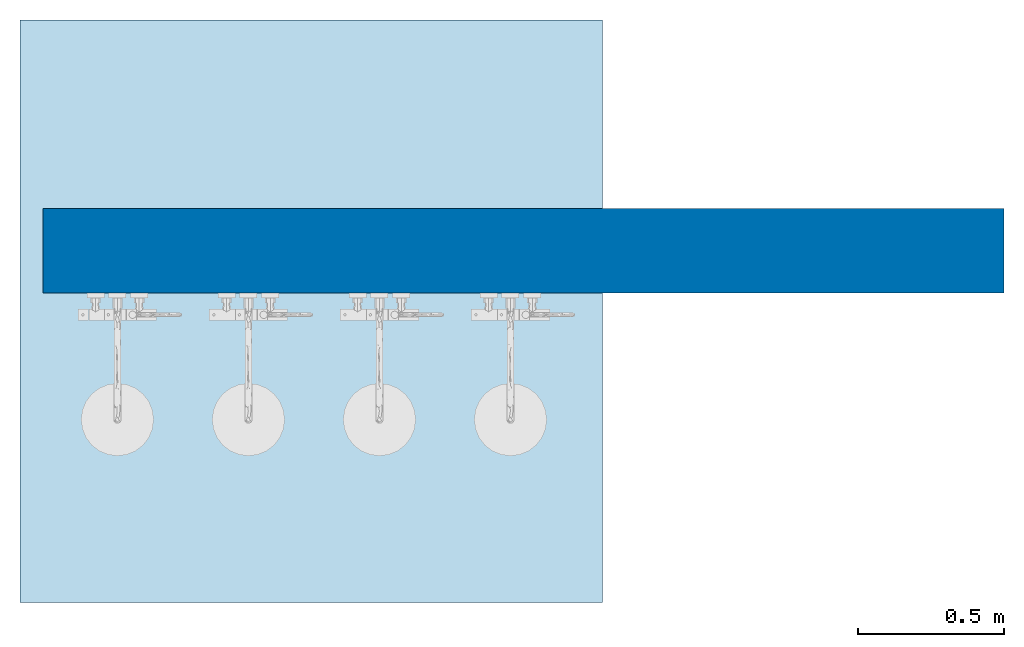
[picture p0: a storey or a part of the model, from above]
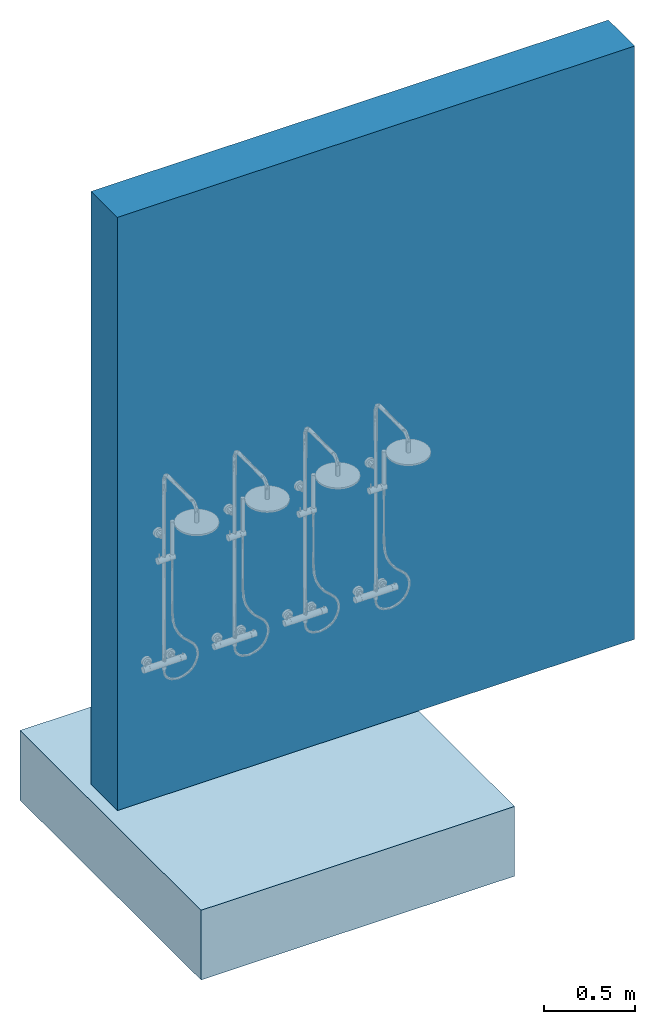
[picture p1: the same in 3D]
Properties of the parts of a building model (IFC2X3)

# File
Description: ViewDefinition [CoordinationView_V2.0]
File name: Project Number
Time: 2023-03-06T11:47:37
Written by: The EXPRESS Data Manager Version 5.02.0100.07 : 28 Aug 2013
Made in: 20220517_1515(x64) - Exporter 20.2.90.12 - Alternate UI 20.2.90.12
Comment: STEP Physical File produced by: The EXPRESS Data Manager Version 5.02.0100.07 : 28 Aug 2013 * Module: EDMstepFileFactory/EDMstandAlone * Creation date: Mon Mar 06 11:47:37 2023 * Host: LAPTOP-F3NQTQR2 * Database: C:\Users\DIANEB~1\AppData\Local\Temp\1c0d499a-c127-429d-b166-6f5f72a16bf1\e90ff138-39aa-4b8e-bb66-7ba3b6e34588\ifc * Database version: 5507 * Database creation date: Mon Mar 06 11:47:32 2023 * Schema: IFC2X3 * Model: DataRepository.ifc * Model creation date: Mon Mar 06 11:47:32 2023 * Header model: DataRepository.ifc_HeaderModel * Header model creation date: Mon Mar 06 11:47:32 2023 * EDMuser: sdai-user * EDMgroup: sdai-group * License ID and type: 5605 : Permanent license. Expiry date: * EDMstepFileFactory options: 020000

# IfcProject, Project Number
LongName: Project Name; Phase: Awaiting Approval

# IfcSite, Default
RefLatitude: 51, 30, 23, 112487; RefLongitude: 0, -7, -37, -956022; RefElevation: 0 mm

# IfcBuilding, n/a
LongName: n/a
Pset_BuildingCommon - NumberOfStoreys: 1
Pset_ProductRequirements - Category: Project Information

# IfcBuildingStorey: Level:Circle Head - Project Datum, Level 0
In: n/a
LongName: Level 0; Elevation: 0 mm
Pset_AirSideSystemInformation - Name: Level 0
Pset_ProductRequirements - Name: Level 0; Category: Levels

# IfcDistributionPort (8)
Description: Flow; FlowDirection: SOURCE
Name
2 x Port_443739
2 x Port_446885
2 x Port_446905
2 x Port_446929

# IfcFlowTerminal: DBLTD_Duten_ShowerHeads_D425:Brushed Brass, DBLTD_Duten_ShowerHeads_D425:Brushed Brass:443739
In: Level 0
Classification: D2010 Plumbing Fixtures (Uniformat); Material: DBLTD_Duten_Metal_BrushedBrass
Pset_DistributionFlowElementCommon - Reference: Brushed Brass; sets with these values: 2
Pset_ElementShading - Color: Brushed Brass
Pset_ManufacturerTypeInformation - ModelReference: Brushed Brass; Manufacturer: contact@duten.fr
Pset_ProductRequirements - Name: Wall Mounted Shower Head; Category: Plumbing Fixtures

# IfcFlowTerminal: DBLTD_Duten_ShowerHeads_D425:Brushed Stainless Steel, DBLTD_Duten_ShowerHeads_D425:Brushed Stainless Steel:446885
In: Level 0
Classification: D2010 Plumbing Fixtures (Uniformat); Material: DBLTD_Duten_Metal_BrushedStainlessSteel
Pset_DistributionFlowElementCommon - Reference: Brushed Stainless Steel; sets with these values: 2
Pset_ElementShading - Color: Brushed Stainless Steel
Pset_ManufacturerTypeInformation - ModelReference: Brushed Stainless Steel; Manufacturer: contact@duten.fr
Pset_ProductRequirements - Name: Wall Mounted Shower Head; Category: Plumbing Fixtures

# IfcFlowTerminal: DBLTD_Duten_ShowerHeads_D425:Chrome, DBLTD_Duten_ShowerHeads_D425:Chrome:446905
In: Level 0
Classification: D2010 Plumbing Fixtures (Uniformat); Material: DBLTD_Duten_Metal_Chrome
Pset_DistributionFlowElementCommon - Reference: Chrome; sets with these values: 2
Pset_ElementShading - Color: Chrome
Pset_ManufacturerTypeInformation - ModelReference: Chrome; Manufacturer: contact@duten.fr
Pset_ProductRequirements - Name: Wall Mounted Shower Head; Category: Plumbing Fixtures

# IfcFlowTerminal: DBLTD_Duten_ShowerHeads_D425:Matte Black, DBLTD_Duten_ShowerHeads_D425:Matte Black:446929
In: Level 0
Classification: D2010 Plumbing Fixtures (Uniformat); Material: DBLTD_Duten_Metal_MatteBlack
Pset_DistributionFlowElementCommon - Reference: Matte Black; sets with these values: 2
Pset_ElementShading - Color: Matte Black
Pset_ManufacturerTypeInformation - ModelReference: Matte Black; Manufacturer: contact@duten.fr
Pset_ProductRequirements - Name: Wall Mounted Shower Head; Category: Plumbing Fixtures

# IfcSlab: Floor:Floor-Grnd-Susp_65Scr-80Ins-100Blk-75PC, Floor:Floor-Grnd-Susp_65Scr-80Ins-100Blk-75PC:421633
In: Level 0
Type - PredefinedType: FLOOR; Material: Concrete, Sand/Cement Screed 65 mm, Rigid insulation 80 mm, Air 150 mm, Concrete Masonry, Floor Block 100 mm, Concrete, Precast 75 mm
Type - Pset_ElementShading - Roughness: 914.4 mm
Type - Pset_ProductRequirements - Category: Floors
Type - Pset_QuantityTakeOff - Reference: Floor-Grnd-Susp_65Scr-80Ins-100Blk-75PC
Type - Pset_ReinforcementBarPitchOfSlab - Reference: Floor-Grnd-Susp_65Scr-80Ins-100Blk-75PC
Type - Pset_SlabCommon - Reference: Floor-Grnd-Susp_65Scr-80Ins-100Blk-75PC; IsExternal: no; ThermalTransmittance: 0.117438 kg/K/s3
Pset_QuantityTakeOff - sets with these values: 2
Pset_SlabCommon - LoadBearing: no; PitchAngle: 0 deg

# IfcWallStandardCase: Basic Wall:Wall-Ext_102Bwk-75Ins-100LBlk-12P, Basic Wall:Wall-Ext_102Bwk-75Ins-100LBlk-12P:432320
In: Level 0
Type - PredefinedType: STANDARD; Material: Brick, Common 102.5 mm, Fiberglass Batt 75 mm, Concrete Masonry Units _Low Density 100 mm, Plaster 12.5 mm
Type - Pset_ElementShading - Roughness: 914.4 mm
Type - Pset_ProductRequirements - Category: Walls
Type - Pset_QuantityTakeOff - Reference: Wall-Ext_102Bwk-75Ins-100LBlk-12P
Type - Pset_ReinforcementBarPitchOfWall - Reference: Wall-Ext_102Bwk-75Ins-100LBlk-12P
Type - Pset_WallCommon - IsExternal: no; Reference: Wall-Ext_102Bwk-75Ins-100LBlk-12P; ThermalTransmittance: 0.235926 kg/K/s3
Pset_QuantityTakeOff - sets with these values: 2
Pset_WallCommon - LoadBearing: no; IsExternal: yes; ExtendToStructure: no
